VERSION 5.8 ;
BUSBITCHARS "[]" ;
DIVIDERCHAR "/" ;

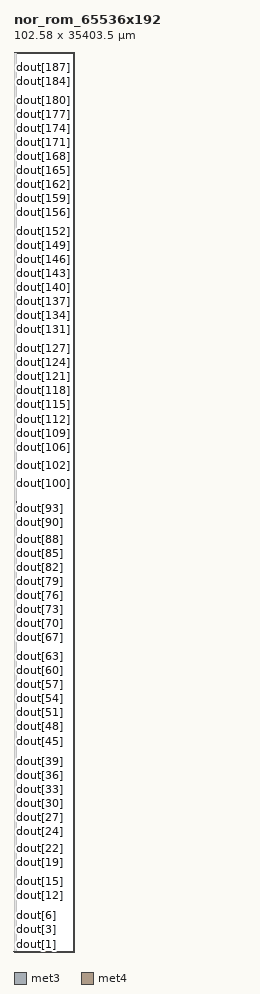
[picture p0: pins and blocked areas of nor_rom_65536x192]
MACRO nor_rom_65536x192
  CLASS BLOCK ;
  ORIGIN 0 0 ;
  SIZE 102.580 BY 35403.520 ;
  SYMMETRY X Y ;

  PIN clk
    DIRECTION INPUT ;
    USE CLOCK ;
    PORT
      LAYER met3 ;
        RECT -0.500 3.000 0.500 3.280 ;
    END
  END clk

  PIN ce
    DIRECTION INPUT ;
    USE SIGNAL ;
    PORT
      LAYER met3 ;
        RECT -0.500 4.000 0.500 4.280 ;
    END
  END ce

  PIN addr[0]
    DIRECTION INPUT ;
    USE SIGNAL ;
    PORT
      LAYER met3 ;
        RECT -0.500 5.000 0.500 5.280 ;
    END
  END addr[0]

  PIN addr[1]
    DIRECTION INPUT ;
    USE SIGNAL ;
    PORT
      LAYER met3 ;
        RECT -0.500 6.000 0.500 6.280 ;
    END
  END addr[1]

  PIN addr[2]
    DIRECTION INPUT ;
    USE SIGNAL ;
    PORT
      LAYER met3 ;
        RECT -0.500 7.000 0.500 7.280 ;
    END
  END addr[2]

  PIN addr[3]
    DIRECTION INPUT ;
    USE SIGNAL ;
    PORT
      LAYER met3 ;
        RECT -0.500 8.000 0.500 8.280 ;
    END
  END addr[3]

  PIN addr[4]
    DIRECTION INPUT ;
    USE SIGNAL ;
    PORT
      LAYER met3 ;
        RECT -0.500 9.000 0.500 9.280 ;
    END
  END addr[4]

  PIN addr[5]
    DIRECTION INPUT ;
    USE SIGNAL ;
    PORT
      LAYER met3 ;
        RECT -0.500 10.000 0.500 10.280 ;
    END
  END addr[5]

  PIN addr[6]
    DIRECTION INPUT ;
    USE SIGNAL ;
    PORT
      LAYER met3 ;
        RECT -0.500 11.000 0.500 11.280 ;
    END
  END addr[6]

  PIN addr[7]
    DIRECTION INPUT ;
    USE SIGNAL ;
    PORT
      LAYER met3 ;
        RECT -0.500 12.000 0.500 12.280 ;
    END
  END addr[7]

  PIN addr[8]
    DIRECTION INPUT ;
    USE SIGNAL ;
    PORT
      LAYER met3 ;
        RECT -0.500 13.000 0.500 13.280 ;
    END
  END addr[8]

  PIN addr[9]
    DIRECTION INPUT ;
    USE SIGNAL ;
    PORT
      LAYER met3 ;
        RECT -0.500 14.000 0.500 14.280 ;
    END
  END addr[9]

  PIN addr[10]
    DIRECTION INPUT ;
    USE SIGNAL ;
    PORT
      LAYER met3 ;
        RECT -0.500 15.000 0.500 15.280 ;
    END
  END addr[10]

  PIN addr[11]
    DIRECTION INPUT ;
    USE SIGNAL ;
    PORT
      LAYER met3 ;
        RECT -0.500 16.000 0.500 16.280 ;
    END
  END addr[11]

  PIN addr[12]
    DIRECTION INPUT ;
    USE SIGNAL ;
    PORT
      LAYER met3 ;
        RECT -0.500 17.000 0.500 17.280 ;
    END
  END addr[12]

  PIN addr[13]
    DIRECTION INPUT ;
    USE SIGNAL ;
    PORT
      LAYER met3 ;
        RECT -0.500 18.000 0.500 18.280 ;
    END
  END addr[13]

  PIN addr[14]
    DIRECTION INPUT ;
    USE SIGNAL ;
    PORT
      LAYER met3 ;
        RECT -0.500 19.000 0.500 19.280 ;
    END
  END addr[14]

  PIN addr[15]
    DIRECTION INPUT ;
    USE SIGNAL ;
    PORT
      LAYER met3 ;
        RECT -0.500 20.000 0.500 20.280 ;
    END
  END addr[15]

  PIN dout[0]
    DIRECTION OUTPUT ;
    USE SIGNAL ;
    PORT
      LAYER met3 ;
        RECT 102.080 3.000 103.080 3.280 ;
    END
  END dout[0]

  PIN dout[1]
    DIRECTION OUTPUT ;
    USE SIGNAL ;
    PORT
      LAYER met3 ;
        RECT 102.080 187.360 103.080 187.640 ;
    END
  END dout[1]

  PIN dout[2]
    DIRECTION OUTPUT ;
    USE SIGNAL ;
    PORT
      LAYER met3 ;
        RECT 102.080 371.720 103.080 372.000 ;
    END
  END dout[2]

  PIN dout[3]
    DIRECTION OUTPUT ;
    USE SIGNAL ;
    PORT
      LAYER met3 ;
        RECT 102.080 556.080 103.080 556.360 ;
    END
  END dout[3]

  PIN dout[4]
    DIRECTION OUTPUT ;
    USE SIGNAL ;
    PORT
      LAYER met3 ;
        RECT 102.080 740.440 103.080 740.720 ;
    END
  END dout[4]

  PIN dout[5]
    DIRECTION OUTPUT ;
    USE SIGNAL ;
    PORT
      LAYER met3 ;
        RECT 102.080 924.800 103.080 925.080 ;
    END
  END dout[5]

  PIN dout[6]
    DIRECTION OUTPUT ;
    USE SIGNAL ;
    PORT
      LAYER met3 ;
        RECT 102.080 1109.160 103.080 1109.440 ;
    END
  END dout[6]

  PIN dout[7]
    DIRECTION OUTPUT ;
    USE SIGNAL ;
    PORT
      LAYER met3 ;
        RECT 102.080 1293.520 103.080 1293.800 ;
    END
  END dout[7]

  PIN dout[8]
    DIRECTION OUTPUT ;
    USE SIGNAL ;
    PORT
      LAYER met3 ;
        RECT 102.080 1477.880 103.080 1478.160 ;
    END
  END dout[8]

  PIN dout[9]
    DIRECTION OUTPUT ;
    USE SIGNAL ;
    PORT
      LAYER met3 ;
        RECT 102.080 1662.240 103.080 1662.520 ;
    END
  END dout[9]

  PIN dout[10]
    DIRECTION OUTPUT ;
    USE SIGNAL ;
    PORT
      LAYER met3 ;
        RECT 102.080 1846.600 103.080 1846.880 ;
    END
  END dout[10]

  PIN dout[11]
    DIRECTION OUTPUT ;
    USE SIGNAL ;
    PORT
      LAYER met3 ;
        RECT 102.080 2030.960 103.080 2031.240 ;
    END
  END dout[11]

  PIN dout[12]
    DIRECTION OUTPUT ;
    USE SIGNAL ;
    PORT
      LAYER met3 ;
        RECT 102.080 2215.320 103.080 2215.600 ;
    END
  END dout[12]

  PIN dout[13]
    DIRECTION OUTPUT ;
    USE SIGNAL ;
    PORT
      LAYER met3 ;
        RECT 102.080 2399.680 103.080 2399.960 ;
    END
  END dout[13]

  PIN dout[14]
    DIRECTION OUTPUT ;
    USE SIGNAL ;
    PORT
      LAYER met3 ;
        RECT 102.080 2584.040 103.080 2584.320 ;
    END
  END dout[14]

  PIN dout[15]
    DIRECTION OUTPUT ;
    USE SIGNAL ;
    PORT
      LAYER met3 ;
        RECT 102.080 2768.400 103.080 2768.680 ;
    END
  END dout[15]

  PIN dout[16]
    DIRECTION OUTPUT ;
    USE SIGNAL ;
    PORT
      LAYER met3 ;
        RECT 102.080 2952.760 103.080 2953.040 ;
    END
  END dout[16]

  PIN dout[17]
    DIRECTION OUTPUT ;
    USE SIGNAL ;
    PORT
      LAYER met3 ;
        RECT 102.080 3137.120 103.080 3137.400 ;
    END
  END dout[17]

  PIN dout[18]
    DIRECTION OUTPUT ;
    USE SIGNAL ;
    PORT
      LAYER met3 ;
        RECT 102.080 3321.480 103.080 3321.760 ;
    END
  END dout[18]

  PIN dout[19]
    DIRECTION OUTPUT ;
    USE SIGNAL ;
    PORT
      LAYER met3 ;
        RECT 102.080 3505.840 103.080 3506.120 ;
    END
  END dout[19]

  PIN dout[20]
    DIRECTION OUTPUT ;
    USE SIGNAL ;
    PORT
      LAYER met3 ;
        RECT 102.080 3690.200 103.080 3690.480 ;
    END
  END dout[20]

  PIN dout[21]
    DIRECTION OUTPUT ;
    USE SIGNAL ;
    PORT
      LAYER met3 ;
        RECT 102.080 3874.560 103.080 3874.840 ;
    END
  END dout[21]

  PIN dout[22]
    DIRECTION OUTPUT ;
    USE SIGNAL ;
    PORT
      LAYER met3 ;
        RECT 102.080 4058.920 103.080 4059.200 ;
    END
  END dout[22]

  PIN dout[23]
    DIRECTION OUTPUT ;
    USE SIGNAL ;
    PORT
      LAYER met3 ;
        RECT 102.080 4243.280 103.080 4243.560 ;
    END
  END dout[23]

  PIN dout[24]
    DIRECTION OUTPUT ;
    USE SIGNAL ;
    PORT
      LAYER met3 ;
        RECT 102.080 4427.640 103.080 4427.920 ;
    END
  END dout[24]

  PIN dout[25]
    DIRECTION OUTPUT ;
    USE SIGNAL ;
    PORT
      LAYER met3 ;
        RECT 102.080 4612.000 103.080 4612.280 ;
    END
  END dout[25]

  PIN dout[26]
    DIRECTION OUTPUT ;
    USE SIGNAL ;
    PORT
      LAYER met3 ;
        RECT 102.080 4796.360 103.080 4796.640 ;
    END
  END dout[26]

  PIN dout[27]
    DIRECTION OUTPUT ;
    USE SIGNAL ;
    PORT
      LAYER met3 ;
        RECT 102.080 4980.720 103.080 4981.000 ;
    END
  END dout[27]

  PIN dout[28]
    DIRECTION OUTPUT ;
    USE SIGNAL ;
    PORT
      LAYER met3 ;
        RECT 102.080 5165.080 103.080 5165.360 ;
    END
  END dout[28]

  PIN dout[29]
    DIRECTION OUTPUT ;
    USE SIGNAL ;
    PORT
      LAYER met3 ;
        RECT 102.080 5349.440 103.080 5349.720 ;
    END
  END dout[29]

  PIN dout[30]
    DIRECTION OUTPUT ;
    USE SIGNAL ;
    PORT
      LAYER met3 ;
        RECT 102.080 5533.800 103.080 5534.080 ;
    END
  END dout[30]

  PIN dout[31]
    DIRECTION OUTPUT ;
    USE SIGNAL ;
    PORT
      LAYER met3 ;
        RECT 102.080 5718.160 103.080 5718.440 ;
    END
  END dout[31]

  PIN dout[32]
    DIRECTION OUTPUT ;
    USE SIGNAL ;
    PORT
      LAYER met3 ;
        RECT 102.080 5902.520 103.080 5902.800 ;
    END
  END dout[32]

  PIN dout[33]
    DIRECTION OUTPUT ;
    USE SIGNAL ;
    PORT
      LAYER met3 ;
        RECT 102.080 6086.880 103.080 6087.160 ;
    END
  END dout[33]

  PIN dout[34]
    DIRECTION OUTPUT ;
    USE SIGNAL ;
    PORT
      LAYER met3 ;
        RECT 102.080 6271.240 103.080 6271.520 ;
    END
  END dout[34]

  PIN dout[35]
    DIRECTION OUTPUT ;
    USE SIGNAL ;
    PORT
      LAYER met3 ;
        RECT 102.080 6455.600 103.080 6455.880 ;
    END
  END dout[35]

  PIN dout[36]
    DIRECTION OUTPUT ;
    USE SIGNAL ;
    PORT
      LAYER met3 ;
        RECT 102.080 6639.960 103.080 6640.240 ;
    END
  END dout[36]

  PIN dout[37]
    DIRECTION OUTPUT ;
    USE SIGNAL ;
    PORT
      LAYER met3 ;
        RECT 102.080 6824.320 103.080 6824.600 ;
    END
  END dout[37]

  PIN dout[38]
    DIRECTION OUTPUT ;
    USE SIGNAL ;
    PORT
      LAYER met3 ;
        RECT 102.080 7008.680 103.080 7008.960 ;
    END
  END dout[38]

  PIN dout[39]
    DIRECTION OUTPUT ;
    USE SIGNAL ;
    PORT
      LAYER met3 ;
        RECT 102.080 7193.040 103.080 7193.320 ;
    END
  END dout[39]

  PIN dout[40]
    DIRECTION OUTPUT ;
    USE SIGNAL ;
    PORT
      LAYER met3 ;
        RECT 102.080 7377.400 103.080 7377.680 ;
    END
  END dout[40]

  PIN dout[41]
    DIRECTION OUTPUT ;
    USE SIGNAL ;
    PORT
      LAYER met3 ;
        RECT 102.080 7561.760 103.080 7562.040 ;
    END
  END dout[41]

  PIN dout[42]
    DIRECTION OUTPUT ;
    USE SIGNAL ;
    PORT
      LAYER met3 ;
        RECT 102.080 7746.120 103.080 7746.400 ;
    END
  END dout[42]

  PIN dout[43]
    DIRECTION OUTPUT ;
    USE SIGNAL ;
    PORT
      LAYER met3 ;
        RECT 102.080 7930.480 103.080 7930.760 ;
    END
  END dout[43]

  PIN dout[44]
    DIRECTION OUTPUT ;
    USE SIGNAL ;
    PORT
      LAYER met3 ;
        RECT 102.080 8114.840 103.080 8115.120 ;
    END
  END dout[44]

  PIN dout[45]
    DIRECTION OUTPUT ;
    USE SIGNAL ;
    PORT
      LAYER met3 ;
        RECT 102.080 8299.200 103.080 8299.480 ;
    END
  END dout[45]

  PIN dout[46]
    DIRECTION OUTPUT ;
    USE SIGNAL ;
    PORT
      LAYER met3 ;
        RECT 102.080 8483.560 103.080 8483.840 ;
    END
  END dout[46]

  PIN dout[47]
    DIRECTION OUTPUT ;
    USE SIGNAL ;
    PORT
      LAYER met3 ;
        RECT 102.080 8667.920 103.080 8668.200 ;
    END
  END dout[47]

  PIN dout[48]
    DIRECTION OUTPUT ;
    USE SIGNAL ;
    PORT
      LAYER met3 ;
        RECT 102.080 8852.280 103.080 8852.560 ;
    END
  END dout[48]

  PIN dout[49]
    DIRECTION OUTPUT ;
    USE SIGNAL ;
    PORT
      LAYER met3 ;
        RECT 102.080 9036.640 103.080 9036.920 ;
    END
  END dout[49]

  PIN dout[50]
    DIRECTION OUTPUT ;
    USE SIGNAL ;
    PORT
      LAYER met3 ;
        RECT 102.080 9221.000 103.080 9221.280 ;
    END
  END dout[50]

  PIN dout[51]
    DIRECTION OUTPUT ;
    USE SIGNAL ;
    PORT
      LAYER met3 ;
        RECT 102.080 9405.360 103.080 9405.640 ;
    END
  END dout[51]

  PIN dout[52]
    DIRECTION OUTPUT ;
    USE SIGNAL ;
    PORT
      LAYER met3 ;
        RECT 102.080 9589.720 103.080 9590.000 ;
    END
  END dout[52]

  PIN dout[53]
    DIRECTION OUTPUT ;
    USE SIGNAL ;
    PORT
      LAYER met3 ;
        RECT 102.080 9774.080 103.080 9774.360 ;
    END
  END dout[53]

  PIN dout[54]
    DIRECTION OUTPUT ;
    USE SIGNAL ;
    PORT
      LAYER met3 ;
        RECT 102.080 9958.440 103.080 9958.720 ;
    END
  END dout[54]

  PIN dout[55]
    DIRECTION OUTPUT ;
    USE SIGNAL ;
    PORT
      LAYER met3 ;
        RECT 102.080 10142.800 103.080 10143.080 ;
    END
  END dout[55]

  PIN dout[56]
    DIRECTION OUTPUT ;
    USE SIGNAL ;
    PORT
      LAYER met3 ;
        RECT 102.080 10327.160 103.080 10327.440 ;
    END
  END dout[56]

  PIN dout[57]
    DIRECTION OUTPUT ;
    USE SIGNAL ;
    PORT
      LAYER met3 ;
        RECT 102.080 10511.520 103.080 10511.800 ;
    END
  END dout[57]

  PIN dout[58]
    DIRECTION OUTPUT ;
    USE SIGNAL ;
    PORT
      LAYER met3 ;
        RECT 102.080 10695.880 103.080 10696.160 ;
    END
  END dout[58]

  PIN dout[59]
    DIRECTION OUTPUT ;
    USE SIGNAL ;
    PORT
      LAYER met3 ;
        RECT 102.080 10880.240 103.080 10880.520 ;
    END
  END dout[59]

  PIN dout[60]
    DIRECTION OUTPUT ;
    USE SIGNAL ;
    PORT
      LAYER met3 ;
        RECT 102.080 11064.600 103.080 11064.880 ;
    END
  END dout[60]

  PIN dout[61]
    DIRECTION OUTPUT ;
    USE SIGNAL ;
    PORT
      LAYER met3 ;
        RECT 102.080 11248.960 103.080 11249.240 ;
    END
  END dout[61]

  PIN dout[62]
    DIRECTION OUTPUT ;
    USE SIGNAL ;
    PORT
      LAYER met3 ;
        RECT 102.080 11433.320 103.080 11433.600 ;
    END
  END dout[62]

  PIN dout[63]
    DIRECTION OUTPUT ;
    USE SIGNAL ;
    PORT
      LAYER met3 ;
        RECT 102.080 11617.680 103.080 11617.960 ;
    END
  END dout[63]

  PIN dout[64]
    DIRECTION OUTPUT ;
    USE SIGNAL ;
    PORT
      LAYER met3 ;
        RECT 102.080 11802.040 103.080 11802.320 ;
    END
  END dout[64]

  PIN dout[65]
    DIRECTION OUTPUT ;
    USE SIGNAL ;
    PORT
      LAYER met3 ;
        RECT 102.080 11986.400 103.080 11986.680 ;
    END
  END dout[65]

  PIN dout[66]
    DIRECTION OUTPUT ;
    USE SIGNAL ;
    PORT
      LAYER met3 ;
        RECT 102.080 12170.760 103.080 12171.040 ;
    END
  END dout[66]

  PIN dout[67]
    DIRECTION OUTPUT ;
    USE SIGNAL ;
    PORT
      LAYER met3 ;
        RECT 102.080 12355.120 103.080 12355.400 ;
    END
  END dout[67]

  PIN dout[68]
    DIRECTION OUTPUT ;
    USE SIGNAL ;
    PORT
      LAYER met3 ;
        RECT 102.080 12539.480 103.080 12539.760 ;
    END
  END dout[68]

  PIN dout[69]
    DIRECTION OUTPUT ;
    USE SIGNAL ;
    PORT
      LAYER met3 ;
        RECT 102.080 12723.840 103.080 12724.120 ;
    END
  END dout[69]

  PIN dout[70]
    DIRECTION OUTPUT ;
    USE SIGNAL ;
    PORT
      LAYER met3 ;
        RECT 102.080 12908.200 103.080 12908.480 ;
    END
  END dout[70]

  PIN dout[71]
    DIRECTION OUTPUT ;
    USE SIGNAL ;
    PORT
      LAYER met3 ;
        RECT 102.080 13092.560 103.080 13092.840 ;
    END
  END dout[71]

  PIN dout[72]
    DIRECTION OUTPUT ;
    USE SIGNAL ;
    PORT
      LAYER met3 ;
        RECT 102.080 13276.920 103.080 13277.200 ;
    END
  END dout[72]

  PIN dout[73]
    DIRECTION OUTPUT ;
    USE SIGNAL ;
    PORT
      LAYER met3 ;
        RECT 102.080 13461.280 103.080 13461.560 ;
    END
  END dout[73]

  PIN dout[74]
    DIRECTION OUTPUT ;
    USE SIGNAL ;
    PORT
      LAYER met3 ;
        RECT 102.080 13645.640 103.080 13645.920 ;
    END
  END dout[74]

  PIN dout[75]
    DIRECTION OUTPUT ;
    USE SIGNAL ;
    PORT
      LAYER met3 ;
        RECT 102.080 13830.000 103.080 13830.280 ;
    END
  END dout[75]

  PIN dout[76]
    DIRECTION OUTPUT ;
    USE SIGNAL ;
    PORT
      LAYER met3 ;
        RECT 102.080 14014.360 103.080 14014.640 ;
    END
  END dout[76]

  PIN dout[77]
    DIRECTION OUTPUT ;
    USE SIGNAL ;
    PORT
      LAYER met3 ;
        RECT 102.080 14198.720 103.080 14199.000 ;
    END
  END dout[77]

  PIN dout[78]
    DIRECTION OUTPUT ;
    USE SIGNAL ;
    PORT
      LAYER met3 ;
        RECT 102.080 14383.080 103.080 14383.360 ;
    END
  END dout[78]

  PIN dout[79]
    DIRECTION OUTPUT ;
    USE SIGNAL ;
    PORT
      LAYER met3 ;
        RECT 102.080 14567.440 103.080 14567.720 ;
    END
  END dout[79]

  PIN dout[80]
    DIRECTION OUTPUT ;
    USE SIGNAL ;
    PORT
      LAYER met3 ;
        RECT 102.080 14751.800 103.080 14752.080 ;
    END
  END dout[80]

  PIN dout[81]
    DIRECTION OUTPUT ;
    USE SIGNAL ;
    PORT
      LAYER met3 ;
        RECT 102.080 14936.160 103.080 14936.440 ;
    END
  END dout[81]

  PIN dout[82]
    DIRECTION OUTPUT ;
    USE SIGNAL ;
    PORT
      LAYER met3 ;
        RECT 102.080 15120.520 103.080 15120.800 ;
    END
  END dout[82]

  PIN dout[83]
    DIRECTION OUTPUT ;
    USE SIGNAL ;
    PORT
      LAYER met3 ;
        RECT 102.080 15304.880 103.080 15305.160 ;
    END
  END dout[83]

  PIN dout[84]
    DIRECTION OUTPUT ;
    USE SIGNAL ;
    PORT
      LAYER met3 ;
        RECT 102.080 15489.240 103.080 15489.520 ;
    END
  END dout[84]

  PIN dout[85]
    DIRECTION OUTPUT ;
    USE SIGNAL ;
    PORT
      LAYER met3 ;
        RECT 102.080 15673.600 103.080 15673.880 ;
    END
  END dout[85]

  PIN dout[86]
    DIRECTION OUTPUT ;
    USE SIGNAL ;
    PORT
      LAYER met3 ;
        RECT 102.080 15857.960 103.080 15858.240 ;
    END
  END dout[86]

  PIN dout[87]
    DIRECTION OUTPUT ;
    USE SIGNAL ;
    PORT
      LAYER met3 ;
        RECT 102.080 16042.320 103.080 16042.600 ;
    END
  END dout[87]

  PIN dout[88]
    DIRECTION OUTPUT ;
    USE SIGNAL ;
    PORT
      LAYER met3 ;
        RECT 102.080 16226.680 103.080 16226.960 ;
    END
  END dout[88]

  PIN dout[89]
    DIRECTION OUTPUT ;
    USE SIGNAL ;
    PORT
      LAYER met3 ;
        RECT 102.080 16411.040 103.080 16411.320 ;
    END
  END dout[89]

  PIN dout[90]
    DIRECTION OUTPUT ;
    USE SIGNAL ;
    PORT
      LAYER met3 ;
        RECT 102.080 16595.400 103.080 16595.680 ;
    END
  END dout[90]

  PIN dout[91]
    DIRECTION OUTPUT ;
    USE SIGNAL ;
    PORT
      LAYER met3 ;
        RECT 102.080 16779.760 103.080 16780.040 ;
    END
  END dout[91]

  PIN dout[92]
    DIRECTION OUTPUT ;
    USE SIGNAL ;
    PORT
      LAYER met3 ;
        RECT 102.080 16964.120 103.080 16964.400 ;
    END
  END dout[92]

  PIN dout[93]
    DIRECTION OUTPUT ;
    USE SIGNAL ;
    PORT
      LAYER met3 ;
        RECT 102.080 17148.480 103.080 17148.760 ;
    END
  END dout[93]

  PIN dout[94]
    DIRECTION OUTPUT ;
    USE SIGNAL ;
    PORT
      LAYER met3 ;
        RECT 102.080 17332.840 103.080 17333.120 ;
    END
  END dout[94]

  PIN dout[95]
    DIRECTION OUTPUT ;
    USE SIGNAL ;
    PORT
      LAYER met3 ;
        RECT 102.080 17517.200 103.080 17517.480 ;
    END
  END dout[95]

  PIN dout[96]
    DIRECTION OUTPUT ;
    USE SIGNAL ;
    PORT
      LAYER met3 ;
        RECT 102.080 17701.560 103.080 17701.840 ;
    END
  END dout[96]

  PIN dout[97]
    DIRECTION OUTPUT ;
    USE SIGNAL ;
    PORT
      LAYER met3 ;
        RECT 102.080 17885.920 103.080 17886.200 ;
    END
  END dout[97]

  PIN dout[98]
    DIRECTION OUTPUT ;
    USE SIGNAL ;
    PORT
      LAYER met3 ;
        RECT 102.080 18070.280 103.080 18070.560 ;
    END
  END dout[98]

  PIN dout[99]
    DIRECTION OUTPUT ;
    USE SIGNAL ;
    PORT
      LAYER met3 ;
        RECT 102.080 18254.640 103.080 18254.920 ;
    END
  END dout[99]

  PIN dout[100]
    DIRECTION OUTPUT ;
    USE SIGNAL ;
    PORT
      LAYER met3 ;
        RECT 102.080 18439.000 103.080 18439.280 ;
    END
  END dout[100]

  PIN dout[101]
    DIRECTION OUTPUT ;
    USE SIGNAL ;
    PORT
      LAYER met3 ;
        RECT 102.080 18623.360 103.080 18623.640 ;
    END
  END dout[101]

  PIN dout[102]
    DIRECTION OUTPUT ;
    USE SIGNAL ;
    PORT
      LAYER met3 ;
        RECT 102.080 18807.720 103.080 18808.000 ;
    END
  END dout[102]

  PIN dout[103]
    DIRECTION OUTPUT ;
    USE SIGNAL ;
    PORT
      LAYER met3 ;
        RECT 102.080 18992.080 103.080 18992.360 ;
    END
  END dout[103]

  PIN dout[104]
    DIRECTION OUTPUT ;
    USE SIGNAL ;
    PORT
      LAYER met3 ;
        RECT 102.080 19176.440 103.080 19176.720 ;
    END
  END dout[104]

  PIN dout[105]
    DIRECTION OUTPUT ;
    USE SIGNAL ;
    PORT
      LAYER met3 ;
        RECT 102.080 19360.800 103.080 19361.080 ;
    END
  END dout[105]

  PIN dout[106]
    DIRECTION OUTPUT ;
    USE SIGNAL ;
    PORT
      LAYER met3 ;
        RECT 102.080 19545.160 103.080 19545.440 ;
    END
  END dout[106]

  PIN dout[107]
    DIRECTION OUTPUT ;
    USE SIGNAL ;
    PORT
      LAYER met3 ;
        RECT 102.080 19729.520 103.080 19729.800 ;
    END
  END dout[107]

  PIN dout[108]
    DIRECTION OUTPUT ;
    USE SIGNAL ;
    PORT
      LAYER met3 ;
        RECT 102.080 19913.880 103.080 19914.160 ;
    END
  END dout[108]

  PIN dout[109]
    DIRECTION OUTPUT ;
    USE SIGNAL ;
    PORT
      LAYER met3 ;
        RECT 102.080 20098.240 103.080 20098.520 ;
    END
  END dout[109]

  PIN dout[110]
    DIRECTION OUTPUT ;
    USE SIGNAL ;
    PORT
      LAYER met3 ;
        RECT 102.080 20282.600 103.080 20282.880 ;
    END
  END dout[110]

  PIN dout[111]
    DIRECTION OUTPUT ;
    USE SIGNAL ;
    PORT
      LAYER met3 ;
        RECT 102.080 20466.960 103.080 20467.240 ;
    END
  END dout[111]

  PIN dout[112]
    DIRECTION OUTPUT ;
    USE SIGNAL ;
    PORT
      LAYER met3 ;
        RECT 102.080 20651.320 103.080 20651.600 ;
    END
  END dout[112]

  PIN dout[113]
    DIRECTION OUTPUT ;
    USE SIGNAL ;
    PORT
      LAYER met3 ;
        RECT 102.080 20835.680 103.080 20835.960 ;
    END
  END dout[113]

  PIN dout[114]
    DIRECTION OUTPUT ;
    USE SIGNAL ;
    PORT
      LAYER met3 ;
        RECT 102.080 21020.040 103.080 21020.320 ;
    END
  END dout[114]

  PIN dout[115]
    DIRECTION OUTPUT ;
    USE SIGNAL ;
    PORT
      LAYER met3 ;
        RECT 102.080 21204.400 103.080 21204.680 ;
    END
  END dout[115]

  PIN dout[116]
    DIRECTION OUTPUT ;
    USE SIGNAL ;
    PORT
      LAYER met3 ;
        RECT 102.080 21388.760 103.080 21389.040 ;
    END
  END dout[116]

  PIN dout[117]
    DIRECTION OUTPUT ;
    USE SIGNAL ;
    PORT
      LAYER met3 ;
        RECT 102.080 21573.120 103.080 21573.400 ;
    END
  END dout[117]

  PIN dout[118]
    DIRECTION OUTPUT ;
    USE SIGNAL ;
    PORT
      LAYER met3 ;
        RECT 102.080 21757.480 103.080 21757.760 ;
    END
  END dout[118]

  PIN dout[119]
    DIRECTION OUTPUT ;
    USE SIGNAL ;
    PORT
      LAYER met3 ;
        RECT 102.080 21941.840 103.080 21942.120 ;
    END
  END dout[119]

  PIN dout[120]
    DIRECTION OUTPUT ;
    USE SIGNAL ;
    PORT
      LAYER met3 ;
        RECT 102.080 22126.200 103.080 22126.480 ;
    END
  END dout[120]

  PIN dout[121]
    DIRECTION OUTPUT ;
    USE SIGNAL ;
    PORT
      LAYER met3 ;
        RECT 102.080 22310.560 103.080 22310.840 ;
    END
  END dout[121]

  PIN dout[122]
    DIRECTION OUTPUT ;
    USE SIGNAL ;
    PORT
      LAYER met3 ;
        RECT 102.080 22494.920 103.080 22495.200 ;
    END
  END dout[122]

  PIN dout[123]
    DIRECTION OUTPUT ;
    USE SIGNAL ;
    PORT
      LAYER met3 ;
        RECT 102.080 22679.280 103.080 22679.560 ;
    END
  END dout[123]

  PIN dout[124]
    DIRECTION OUTPUT ;
    USE SIGNAL ;
    PORT
      LAYER met3 ;
        RECT 102.080 22863.640 103.080 22863.920 ;
    END
  END dout[124]

  PIN dout[125]
    DIRECTION OUTPUT ;
    USE SIGNAL ;
    PORT
      LAYER met3 ;
        RECT 102.080 23048.000 103.080 23048.280 ;
    END
  END dout[125]

  PIN dout[126]
    DIRECTION OUTPUT ;
    USE SIGNAL ;
    PORT
      LAYER met3 ;
        RECT 102.080 23232.360 103.080 23232.640 ;
    END
  END dout[126]

  PIN dout[127]
    DIRECTION OUTPUT ;
    USE SIGNAL ;
    PORT
      LAYER met3 ;
        RECT 102.080 23416.720 103.080 23417.000 ;
    END
  END dout[127]

  PIN dout[128]
    DIRECTION OUTPUT ;
    USE SIGNAL ;
    PORT
      LAYER met3 ;
        RECT 102.080 23601.080 103.080 23601.360 ;
    END
  END dout[128]

  PIN dout[129]
    DIRECTION OUTPUT ;
    USE SIGNAL ;
    PORT
      LAYER met3 ;
        RECT 102.080 23785.440 103.080 23785.720 ;
    END
  END dout[129]

  PIN dout[130]
    DIRECTION OUTPUT ;
    USE SIGNAL ;
    PORT
      LAYER met3 ;
        RECT 102.080 23969.800 103.080 23970.080 ;
    END
  END dout[130]

  PIN dout[131]
    DIRECTION OUTPUT ;
    USE SIGNAL ;
    PORT
      LAYER met3 ;
        RECT 102.080 24154.160 103.080 24154.440 ;
    END
  END dout[131]

  PIN dout[132]
    DIRECTION OUTPUT ;
    USE SIGNAL ;
    PORT
      LAYER met3 ;
        RECT 102.080 24338.520 103.080 24338.800 ;
    END
  END dout[132]

  PIN dout[133]
    DIRECTION OUTPUT ;
    USE SIGNAL ;
    PORT
      LAYER met3 ;
        RECT 102.080 24522.880 103.080 24523.160 ;
    END
  END dout[133]

  PIN dout[134]
    DIRECTION OUTPUT ;
    USE SIGNAL ;
    PORT
      LAYER met3 ;
        RECT 102.080 24707.240 103.080 24707.520 ;
    END
  END dout[134]

  PIN dout[135]
    DIRECTION OUTPUT ;
    USE SIGNAL ;
    PORT
      LAYER met3 ;
        RECT 102.080 24891.600 103.080 24891.880 ;
    END
  END dout[135]

  PIN dout[136]
    DIRECTION OUTPUT ;
    USE SIGNAL ;
    PORT
      LAYER met3 ;
        RECT 102.080 25075.960 103.080 25076.240 ;
    END
  END dout[136]

  PIN dout[137]
    DIRECTION OUTPUT ;
    USE SIGNAL ;
    PORT
      LAYER met3 ;
        RECT 102.080 25260.320 103.080 25260.600 ;
    END
  END dout[137]

  PIN dout[138]
    DIRECTION OUTPUT ;
    USE SIGNAL ;
    PORT
      LAYER met3 ;
        RECT 102.080 25444.680 103.080 25444.960 ;
    END
  END dout[138]

  PIN dout[139]
    DIRECTION OUTPUT ;
    USE SIGNAL ;
    PORT
      LAYER met3 ;
        RECT 102.080 25629.040 103.080 25629.320 ;
    END
  END dout[139]

  PIN dout[140]
    DIRECTION OUTPUT ;
    USE SIGNAL ;
    PORT
      LAYER met3 ;
        RECT 102.080 25813.400 103.080 25813.680 ;
    END
  END dout[140]

  PIN dout[141]
    DIRECTION OUTPUT ;
    USE SIGNAL ;
    PORT
      LAYER met3 ;
        RECT 102.080 25997.760 103.080 25998.040 ;
    END
  END dout[141]

  PIN dout[142]
    DIRECTION OUTPUT ;
    USE SIGNAL ;
    PORT
      LAYER met3 ;
        RECT 102.080 26182.120 103.080 26182.400 ;
    END
  END dout[142]

  PIN dout[143]
    DIRECTION OUTPUT ;
    USE SIGNAL ;
    PORT
      LAYER met3 ;
        RECT 102.080 26366.480 103.080 26366.760 ;
    END
  END dout[143]

  PIN dout[144]
    DIRECTION OUTPUT ;
    USE SIGNAL ;
    PORT
      LAYER met3 ;
        RECT 102.080 26550.840 103.080 26551.120 ;
    END
  END dout[144]

  PIN dout[145]
    DIRECTION OUTPUT ;
    USE SIGNAL ;
    PORT
      LAYER met3 ;
        RECT 102.080 26735.200 103.080 26735.480 ;
    END
  END dout[145]

  PIN dout[146]
    DIRECTION OUTPUT ;
    USE SIGNAL ;
    PORT
      LAYER met3 ;
        RECT 102.080 26919.560 103.080 26919.840 ;
    END
  END dout[146]

  PIN dout[147]
    DIRECTION OUTPUT ;
    USE SIGNAL ;
    PORT
      LAYER met3 ;
        RECT 102.080 27103.920 103.080 27104.200 ;
    END
  END dout[147]

  PIN dout[148]
    DIRECTION OUTPUT ;
    USE SIGNAL ;
    PORT
      LAYER met3 ;
        RECT 102.080 27288.280 103.080 27288.560 ;
    END
  END dout[148]

  PIN dout[149]
    DIRECTION OUTPUT ;
    USE SIGNAL ;
    PORT
      LAYER met3 ;
        RECT 102.080 27472.640 103.080 27472.920 ;
    END
  END dout[149]

  PIN dout[150]
    DIRECTION OUTPUT ;
    USE SIGNAL ;
    PORT
      LAYER met3 ;
        RECT 102.080 27657.000 103.080 27657.280 ;
    END
  END dout[150]

  PIN dout[151]
    DIRECTION OUTPUT ;
    USE SIGNAL ;
    PORT
      LAYER met3 ;
        RECT 102.080 27841.360 103.080 27841.640 ;
    END
  END dout[151]

  PIN dout[152]
    DIRECTION OUTPUT ;
    USE SIGNAL ;
    PORT
      LAYER met3 ;
        RECT 102.080 28025.720 103.080 28026.000 ;
    END
  END dout[152]

  PIN dout[153]
    DIRECTION OUTPUT ;
    USE SIGNAL ;
    PORT
      LAYER met3 ;
        RECT 102.080 28210.080 103.080 28210.360 ;
    END
  END dout[153]

  PIN dout[154]
    DIRECTION OUTPUT ;
    USE SIGNAL ;
    PORT
      LAYER met3 ;
        RECT 102.080 28394.440 103.080 28394.720 ;
    END
  END dout[154]

  PIN dout[155]
    DIRECTION OUTPUT ;
    USE SIGNAL ;
    PORT
      LAYER met3 ;
        RECT 102.080 28578.800 103.080 28579.080 ;
    END
  END dout[155]

  PIN dout[156]
    DIRECTION OUTPUT ;
    USE SIGNAL ;
    PORT
      LAYER met3 ;
        RECT 102.080 28763.160 103.080 28763.440 ;
    END
  END dout[156]

  PIN dout[157]
    DIRECTION OUTPUT ;
    USE SIGNAL ;
    PORT
      LAYER met3 ;
        RECT 102.080 28947.520 103.080 28947.800 ;
    END
  END dout[157]

  PIN dout[158]
    DIRECTION OUTPUT ;
    USE SIGNAL ;
    PORT
      LAYER met3 ;
        RECT 102.080 29131.880 103.080 29132.160 ;
    END
  END dout[158]

  PIN dout[159]
    DIRECTION OUTPUT ;
    USE SIGNAL ;
    PORT
      LAYER met3 ;
        RECT 102.080 29316.240 103.080 29316.520 ;
    END
  END dout[159]

  PIN dout[160]
    DIRECTION OUTPUT ;
    USE SIGNAL ;
    PORT
      LAYER met3 ;
        RECT 102.080 29500.600 103.080 29500.880 ;
    END
  END dout[160]

  PIN dout[161]
    DIRECTION OUTPUT ;
    USE SIGNAL ;
    PORT
      LAYER met3 ;
        RECT 102.080 29684.960 103.080 29685.240 ;
    END
  END dout[161]

  PIN dout[162]
    DIRECTION OUTPUT ;
    USE SIGNAL ;
    PORT
      LAYER met3 ;
        RECT 102.080 29869.320 103.080 29869.600 ;
    END
  END dout[162]

  PIN dout[163]
    DIRECTION OUTPUT ;
    USE SIGNAL ;
    PORT
      LAYER met3 ;
        RECT 102.080 30053.680 103.080 30053.960 ;
    END
  END dout[163]

  PIN dout[164]
    DIRECTION OUTPUT ;
    USE SIGNAL ;
    PORT
      LAYER met3 ;
        RECT 102.080 30238.040 103.080 30238.320 ;
    END
  END dout[164]

  PIN dout[165]
    DIRECTION OUTPUT ;
    USE SIGNAL ;
    PORT
      LAYER met3 ;
        RECT 102.080 30422.400 103.080 30422.680 ;
    END
  END dout[165]

  PIN dout[166]
    DIRECTION OUTPUT ;
    USE SIGNAL ;
    PORT
      LAYER met3 ;
        RECT 102.080 30606.760 103.080 30607.040 ;
    END
  END dout[166]

  PIN dout[167]
    DIRECTION OUTPUT ;
    USE SIGNAL ;
    PORT
      LAYER met3 ;
        RECT 102.080 30791.120 103.080 30791.400 ;
    END
  END dout[167]

  PIN dout[168]
    DIRECTION OUTPUT ;
    USE SIGNAL ;
    PORT
      LAYER met3 ;
        RECT 102.080 30975.480 103.080 30975.760 ;
    END
  END dout[168]

  PIN dout[169]
    DIRECTION OUTPUT ;
    USE SIGNAL ;
    PORT
      LAYER met3 ;
        RECT 102.080 31159.840 103.080 31160.120 ;
    END
  END dout[169]

  PIN dout[170]
    DIRECTION OUTPUT ;
    USE SIGNAL ;
    PORT
      LAYER met3 ;
        RECT 102.080 31344.200 103.080 31344.480 ;
    END
  END dout[170]

  PIN dout[171]
    DIRECTION OUTPUT ;
    USE SIGNAL ;
    PORT
      LAYER met3 ;
        RECT 102.080 31528.560 103.080 31528.840 ;
    END
  END dout[171]

  PIN dout[172]
    DIRECTION OUTPUT ;
    USE SIGNAL ;
    PORT
      LAYER met3 ;
        RECT 102.080 31712.920 103.080 31713.200 ;
    END
  END dout[172]

  PIN dout[173]
    DIRECTION OUTPUT ;
    USE SIGNAL ;
    PORT
      LAYER met3 ;
        RECT 102.080 31897.280 103.080 31897.560 ;
    END
  END dout[173]

  PIN dout[174]
    DIRECTION OUTPUT ;
    USE SIGNAL ;
    PORT
      LAYER met3 ;
        RECT 102.080 32081.640 103.080 32081.920 ;
    END
  END dout[174]

  PIN dout[175]
    DIRECTION OUTPUT ;
    USE SIGNAL ;
    PORT
      LAYER met3 ;
        RECT 102.080 32266.000 103.080 32266.280 ;
    END
  END dout[175]

  PIN dout[176]
    DIRECTION OUTPUT ;
    USE SIGNAL ;
    PORT
      LAYER met3 ;
        RECT 102.080 32450.360 103.080 32450.640 ;
    END
  END dout[176]

  PIN dout[177]
    DIRECTION OUTPUT ;
    USE SIGNAL ;
    PORT
      LAYER met3 ;
        RECT 102.080 32634.720 103.080 32635.000 ;
    END
  END dout[177]

  PIN dout[178]
    DIRECTION OUTPUT ;
    USE SIGNAL ;
    PORT
      LAYER met3 ;
        RECT 102.080 32819.080 103.080 32819.360 ;
    END
  END dout[178]

  PIN dout[179]
    DIRECTION OUTPUT ;
    USE SIGNAL ;
    PORT
      LAYER met3 ;
        RECT 102.080 33003.440 103.080 33003.720 ;
    END
  END dout[179]

  PIN dout[180]
    DIRECTION OUTPUT ;
    USE SIGNAL ;
    PORT
      LAYER met3 ;
        RECT 102.080 33187.800 103.080 33188.080 ;
    END
  END dout[180]

  PIN dout[181]
    DIRECTION OUTPUT ;
    USE SIGNAL ;
    PORT
      LAYER met3 ;
        RECT 102.080 33372.160 103.080 33372.440 ;
    END
  END dout[181]

  PIN dout[182]
    DIRECTION OUTPUT ;
    USE SIGNAL ;
    PORT
      LAYER met3 ;
        RECT 102.080 33556.520 103.080 33556.800 ;
    END
  END dout[182]

  PIN dout[183]
    DIRECTION OUTPUT ;
    USE SIGNAL ;
    PORT
      LAYER met3 ;
        RECT 102.080 33740.880 103.080 33741.160 ;
    END
  END dout[183]

  PIN dout[184]
    DIRECTION OUTPUT ;
    USE SIGNAL ;
    PORT
      LAYER met3 ;
        RECT 102.080 33925.240 103.080 33925.520 ;
    END
  END dout[184]

  PIN dout[185]
    DIRECTION OUTPUT ;
    USE SIGNAL ;
    PORT
      LAYER met3 ;
        RECT 102.080 34109.600 103.080 34109.880 ;
    END
  END dout[185]

  PIN dout[186]
    DIRECTION OUTPUT ;
    USE SIGNAL ;
    PORT
      LAYER met3 ;
        RECT 102.080 34293.960 103.080 34294.240 ;
    END
  END dout[186]

  PIN dout[187]
    DIRECTION OUTPUT ;
    USE SIGNAL ;
    PORT
      LAYER met3 ;
        RECT 102.080 34478.320 103.080 34478.600 ;
    END
  END dout[187]

  PIN dout[188]
    DIRECTION OUTPUT ;
    USE SIGNAL ;
    PORT
      LAYER met3 ;
        RECT 102.080 34662.680 103.080 34662.960 ;
    END
  END dout[188]

  PIN dout[189]
    DIRECTION OUTPUT ;
    USE SIGNAL ;
    PORT
      LAYER met3 ;
        RECT 102.080 34847.040 103.080 34847.320 ;
    END
  END dout[189]

  PIN dout[190]
    DIRECTION OUTPUT ;
    USE SIGNAL ;
    PORT
      LAYER met3 ;
        RECT 102.080 35031.400 103.080 35031.680 ;
    END
  END dout[190]

  PIN dout[191]
    DIRECTION OUTPUT ;
    USE SIGNAL ;
    PORT
      LAYER met3 ;
        RECT 102.080 35215.760 103.080 35216.040 ;
    END
  END dout[191]

  PIN VDD
    DIRECTION INOUT ;
    USE POWER ;
    PORT
      LAYER met4 ;
        RECT 0.000 35402.520 102.580 35403.520 ;
    END
  END VDD

  PIN VSS
    DIRECTION INOUT ;
    USE GROUND ;
    PORT
      LAYER met4 ;
        RECT 0.000 0.000 102.580 1.000 ;
    END
  END VSS

  OBS
    LAYER met1 ;
      RECT 2.000 2.000 100.580 35401.520 ;
    LAYER met2 ;
      RECT 2.000 2.000 100.580 35401.520 ;
  END

END nor_rom_65536x192

END LIBRARY
